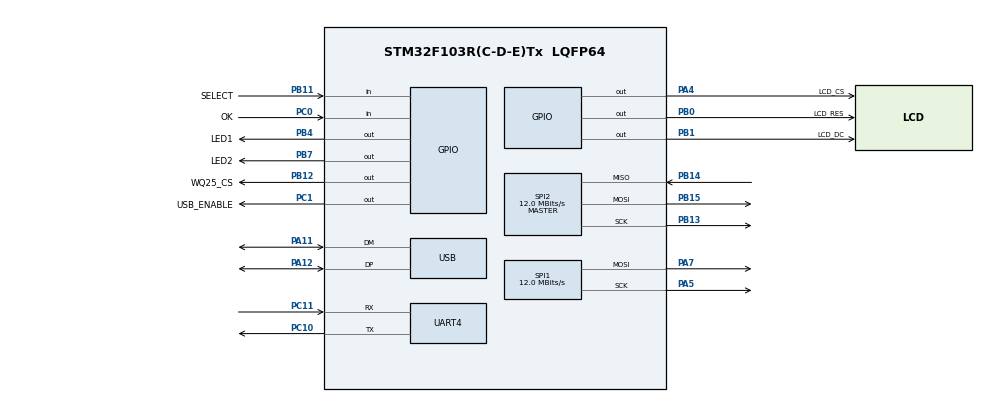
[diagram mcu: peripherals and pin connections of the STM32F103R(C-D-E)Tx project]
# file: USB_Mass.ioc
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Dma.Request0=SPI1_TX
Dma.SPI1_TX.0.Direction=DMA_MEMORY_TO_PERIPH
Dma.SPI1_TX.0.Instance=DMA1_Channel3
Dma.SPI1_TX.0.MemDataAlignment=DMA_MDATAALIGN_BYTE
Dma.SPI1_TX.0.MemInc=DMA_MINC_ENABLE
Dma.SPI1_TX.0.Mode=DMA_NORMAL
Dma.SPI1_TX.0.PeriphDataAlignment=DMA_PDATAALIGN_BYTE
Dma.SPI1_TX.0.PeriphInc=DMA_PINC_DISABLE
Dma.SPI1_TX.0.Priority=DMA_PRIORITY_HIGH
FATFS._MAX_SS=4096
FATFS._MIN_SS=4096
Mcu.Family=STM32F1
Mcu.Name=STM32F103R(C-D-E)Tx
Mcu.Package=LQFP64
NVIC.DMA1_Channel3_IRQn=true\:0\:0\:false\:false\:true\:false\:true\:true
NVIC.PriorityGroup=NVIC_PRIORITYGROUP_4
NVIC.TIM3_IRQn=true\:0\:0\:false\:false\:true\:true\:true\:true
NVIC.USB_LP_CAN1_RX0_IRQn=true\:0\:0\:false\:false\:true\:false\:true\:true
PA11.Mode=Device
PA11.Signal=USB_DM
PA12.Mode=Device
PA12.Signal=USB_DP
PA13.Mode=Serial_Wire
PA13.Signal=SYS_JTMS-SWDIO
PA14.Mode=Serial_Wire
PA14.Signal=SYS_JTCK-SWCLK
PA4.GPIO_Label=LCD_CS
PA4.GPIO_Speed=GPIO_SPEED_FREQ_HIGH
PA4.Signal=GPIO_Output
PA5.Mode=TX_Only_Simplex_Unidirect_Master
PA5.Signal=SPI1_SCK
PA7.Mode=TX_Only_Simplex_Unidirect_Master
PA7.Signal=SPI1_MOSI
PB0.GPIO_Label=LCD_RES
PB0.GPIO_Speed=GPIO_SPEED_FREQ_HIGH
PB0.Signal=GPIO_Output
PB1.GPIO_Label=LCD_DC
PB1.GPIO_Speed=GPIO_SPEED_FREQ_HIGH
PB1.Signal=GPIO_Output
PB11.GPIO_Label=SELECT
PB11.GPIO_PuPd=GPIO_PULLUP
PB11.Signal=GPIO_Input
PB12.GPIO_Label=WQ25_CS
PB12.GPIO_Speed=GPIO_SPEED_FREQ_HIGH
PB12.Signal=GPIO_Output
PB13.Mode=Full_Duplex_Master
PB13.Signal=SPI2_SCK
PB14.Mode=Full_Duplex_Master
PB14.Signal=SPI2_MISO
PB15.Mode=Full_Duplex_Master
PB15.Signal=SPI2_MOSI
PB4.GPIO_Label=LED1
PB4.GPIO_Speed=GPIO_SPEED_FREQ_HIGH
PB4.PinState=GPIO_PIN_SET
PB4.Signal=GPIO_Output
PB7.GPIO_Label=LED2
PB7.GPIO_Speed=GPIO_SPEED_FREQ_HIGH
PB7.PinState=GPIO_PIN_SET
PB7.Signal=GPIO_Output
PC0.GPIO_Label=OK
PC0.GPIO_PuPd=GPIO_PULLUP
PC0.Signal=GPIO_Input
PC1.GPIO_Label=USB_ENABLE
PC1.GPIO_Speed=GPIO_SPEED_FREQ_HIGH
PC1.PinState=GPIO_PIN_RESET
PC1.Signal=GPIO_Output
PC10.Mode=Asynchronous
PC10.Signal=UART4_TX
PC11.Mode=Asynchronous
PC11.Signal=UART4_RX
PD0-OSC_IN.Mode=HSE-External-Oscillator
PD0-OSC_IN.Signal=RCC_OSC_IN
PD1-OSC_OUT.Mode=HSE-External-Oscillator
PD1-OSC_OUT.Signal=RCC_OSC_OUT
ProjectManager.HeapSize=0x200
ProjectManager.StackSize=0x400
ProjectManager.TargetToolchain=MDK-ARM V5.32
RCC.AHBFreq_Value=48000000
RCC.APB1CLKDivider=RCC_HCLK_DIV2
RCC.APB1Freq_Value=24000000
RCC.APB1TimFreq_Value=48000000
RCC.APB2Freq_Value=48000000
RCC.APB2TimFreq_Value=48000000
RCC.HCLKFreq_Value=48000000
RCC.PLLMUL=RCC_PLL_MUL6
RCC.SYSCLKFreq_VALUE=48000000
RCC.SYSCLKSource=RCC_SYSCLKSOURCE_PLLCLK
RCC.USBFreq_Value=48000000
SPI1.BaudRatePrescaler=SPI_BAUDRATEPRESCALER_4
SPI1.CLKPhase=SPI_PHASE_2EDGE
SPI1.CLKPolarity=SPI_POLARITY_HIGH
SPI1.CRCCalculation=SPI_CRCCALCULATION_DISABLE
SPI1.CalculateBaudRate=12.0 MBits/s
SPI1.DataSize=SPI_DATASIZE_8BIT
SPI1.Direction=SPI_DIRECTION_2LINES
SPI1.Mode=SPI_MODE_MASTER
SPI1.VirtualType=VM_MASTER
SPI2.BaudRatePrescaler=SPI_BAUDRATEPRESCALER_2
SPI2.CLKPhase=SPI_PHASE_2EDGE
SPI2.CLKPolarity=SPI_POLARITY_HIGH
SPI2.CalculateBaudRate=12.0 MBits/s
SPI2.Direction=SPI_DIRECTION_2LINES
SPI2.Mode=SPI_MODE_MASTER
SPI2.VirtualType=VM_MASTER
TIM3.Period=1000-1
TIM3.Prescaler=48-1
UART4.VirtualMode=Asynchronous
USB_DEVICE.CLASS_NAME_FS=MSC
USB_DEVICE.MSC_MEDIA_PACKET=4096
USB_DEVICE.VirtualMode=Msc
USB_DEVICE.VirtualModeFS=Msc_FS
VP_FATFS_VS_Generic.Mode=User_defined
VP_TIM3_VS_ClockSourceINT.Mode=Internal
VP_USB_DEVICE_VS_USB_DEVICE_MSC_FS.Mode=MSC_FS
board=custom

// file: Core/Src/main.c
/* USER CODE BEGIN Header */
/**
  ******************************************************************************
  * @file           : main.c
  * @brief          : Main program body
  ******************************************************************************
  * @attention
  *
  * Copyright (c) 2025 STMicroelectronics.
  * All rights reserved.
  *
  * This software is licensed under terms that can be found in the LICENSE file
  * in the root directory of this software component.
  * If no LICENSE file comes with this software, it is provided AS-IS.
  *
  ******************************************************************************
  */
/* USER CODE END Header */
#include "main.h"
#include "dma.h"
#include "fatfs.h"
#include "spi.h"
#include "tim.h"
#include "usart.h"
#include "usb_device.h"
#include "gpio.h"

/* USER CODE BEGIN Includes */
#include "w25qxx.h"
#include "lvgl_ui.h"
#include "json_app.h"
#include "hal/lv_hal_tick.h"
#include "usbd_cdc_if.h"
#include <string.h>
#include <stdio.h>

/* FreeRTOS 头文件 */
#include "FreeRTOS.h"
#include "task.h"
#include "semphr.h"
/* 文件服务 */
#include "app_file_service.h"
/* LVGL 和 LCD 函数声明 */
#include "lvgl.h"
#include "lv_port_disp.h"
#include "lv_port_indev.h"
#include "lcd_init.h"
/* USER CODE END Includes */

/* USER CODE BEGIN PM */
uint8_t file_res;
uint8_t flag = 0;
uint8_t file_res_1;
uint8_t file_res_2;
uint8_t file_res_3;
FILINFO FileInfo = {0};
DIR DirInfo;
DIR User_DirInfo;
FATFS fs; /* Work area (file system object) for logical drives */
FRESULT Res;
UINT br, bw; /* File R/W count */
BYTE work[_MAX_SS];
uint8_t Ctrl_CDC=0;

/* FreeRTOS 任务句柄 */
static TaskHandle_t lvgl_task_handle = NULL;
TaskHandle_t g_cdc_tx_task_handle = NULL;  /* 全局，用于 ISR 通知 */
/* USER CODE END PM */

void SystemClock_Config(void);
/* USER CODE BEGIN PFP */
static void LvglTask(void *argument);
static void CdcTxTask(void *argument);
static void LedTask(void *argument);
/* USER CODE END PFP */

/* USER CODE BEGIN 0 */
#if _USE_LFN
WCHAR ff_convert(WCHAR chr, UINT dir)
{
    if (dir == 0) {
        // 多字节(ASCII) → UTF-16：直接返回（ASCII编码值=UTF-16低字节）
        return (chr <= 0x7F) ? chr : 0;
    } else {
        // UTF-16 → 多字节(ASCII)：仅返回低字节（过滤非ASCII字符）
        return (chr <= 0x7F) ? chr : 0;
    }
}

WCHAR ff_wtoupper (WCHAR chr)
{
    // 判断是否为小写英文字母（UTF-16中a-z的编码为0x0061~0x007A）
    if (chr >= 0x0061 && chr <= 0x007A) {
        return chr - 0x0020;  // 转为大写（A-Z：0x0041~0x005A）
    }
    // 其他字符（数字、符号、中文等）不转换，原样返回
    return chr;
}
#endif
/* USER CODE END 0 */

int main(void)
{

    /* MCU Configuration--------------------------------------------------------*/

    /* Reset of all peripherals, Initializes the Flash interface and the Systick. */
    HAL_Init();

    /* Configure the system clock */
    SystemClock_Config();

    /* Initialize all configured peripherals */
    MX_GPIO_Init();
    MX_DMA_Init();
    MX_SPI2_Init();
    MX_UART4_Init();
    MX_FATFS_Init();
    MX_TIM3_Init();
    HAL_TIM_Base_Start_IT(&htim3);  /* 必须先启动 TIM3，HAL_Delay 依赖它 */
    MX_USB_DEVICE_Init();
    MX_SPI1_Init();
    /* USER CODE BEGIN 2 */

    SPI_FLASH_CS_HIGH();
    W25QXX_TYPE = SPI_FLASH_ReadID();

    file_res = f_mount(&fs, "0:", 1);
    if (FR_NO_FILESYSTEM == file_res)
    {
        flag = 1;
        file_res_1 = f_mkfs("0:", 0, sizeof(work));
        file_res_2 = f_mount(NULL, "0:", 1);
        file_res_3 = f_mount(&fs, "0:", 1);
    }
    HAL_GPIO_WritePin(USB_ENABLE_GPIO_Port, USB_ENABLE_Pin, GPIO_PIN_RESET);
    HAL_Delay(50);  /* 等待主机检测到 USB D+ 上拉 */

    LCD_Init();
    lv_init();            // LVGL 初始化
    lv_port_disp_init();  // 注册LVGL的显示任务
    lv_port_indev_init(); // 按键注册

    create_test_ui();

    if (f_opendir(&DirInfo, (const TCHAR *)"0:") == FR_OK) /* 打开文件夹目录成功，目录信息已经在dir结构体中保存 */
        f_readdir(&DirInfo, &FileInfo); /* 读文件信息到文件状态结构体中 */

//    test_json_parser(); // 测试 json_parser

    /* USER CODE END 2 */

    /* Infinite loop */
    /* USER CODE BEGIN WHILE */
    /* CDC 接收计数信号量（用于 ISR→Task 数据传递）*/
    CDC_Init();

    /* 初始化文件服务任务（优先级 1，用于 FATFS 操作）*/
    FS_Init();

    /* 学习点：FreeRTOS 启动流程
     *
     * 1. xTaskCreate() — 创建任务
     *    参数：任务函数，任务名，栈深度(words)，参数，优先级，任务句柄
     *    LVGL 任务优先级设为 2（空闲任务=0，定时器服务任务=4）
     *
     * 2. vTaskStartScheduler() — 启动 FreeRTOS 调度器
     *    此函数会创建空闲任务和定时器服务任务（如果启用），
     *    然后通过 SVC 异常启动第一个任务。
     *    调用后不会再返回！
     */
    xTaskCreate(
        LvglTask,
        "LVGL",
        440,
        NULL,
        2,
        &lvgl_task_handle
    );

    /* 学习点：CDC TX 任务使用任务通知替代轮询
     * 优先级 3 > LVGL(2)，确保 USB 回传低延迟
     * 当无数据时阻塞在 ulTaskNotifyTake，不消耗 CPU */
    xTaskCreate(
        CdcTxTask,
        "CDC_TX",
        256,
        NULL,
        3,
        &g_cdc_tx_task_handle
    );

    xTaskCreate(
        LedTask,
        "LED",
        80,
        NULL,
        1,
        NULL
    );

    vTaskStartScheduler();  /* 启动调度器，不会返回 */

    /* 如果执行到这里说明 FreeRTOS 堆内存不足 */
    Error_Handler();
    /* USER CODE END WHILE */

}

void SystemClock_Config(void)
{
    RCC_OscInitTypeDef RCC_OscInitStruct = {0};
    RCC_ClkInitTypeDef RCC_ClkInitStruct = {0};
    RCC_PeriphCLKInitTypeDef PeriphClkInit = {0};

    /** Initializes the RCC Oscillators according to the specified parameters
     * in the RCC_OscInitTypeDef structure.
     */
    RCC_OscInitStruct.OscillatorType = RCC_OSCILLATORTYPE_HSE;
    RCC_OscInitStruct.HSEState = RCC_HSE_ON;
    RCC_OscInitStruct.HSEPredivValue = RCC_HSE_PREDIV_DIV1;
    RCC_OscInitStruct.HSIState = RCC_HSI_ON;
    RCC_OscInitStruct.PLL.PLLState = RCC_PLL_ON;
    RCC_OscInitStruct.PLL.PLLSource = RCC_PLLSOURCE_HSE;
    RCC_OscInitStruct.PLL.PLLMUL = RCC_PLL_MUL9;
    if (HAL_RCC_OscConfig(&RCC_OscInitStruct) != HAL_OK)
    {
        Error_Handler();
    }

    /** Initializes the CPU, AHB and APB buses clocks
     */
    RCC_ClkInitStruct.ClockType = RCC_CLOCKTYPE_HCLK | RCC_CLOCKTYPE_SYSCLK | RCC_CLOCKTYPE_PCLK1 | RCC_CLOCKTYPE_PCLK2;
    RCC_ClkInitStruct.SYSCLKSource = RCC_SYSCLKSOURCE_PLLCLK;
    RCC_ClkInitStruct.AHBCLKDivider = RCC_SYSCLK_DIV1;
    RCC_ClkInitStruct.APB1CLKDivider = RCC_HCLK_DIV2;
    RCC_ClkInitStruct.APB2CLKDivider = RCC_HCLK_DIV1;

    if (HAL_RCC_ClockConfig(&RCC_ClkInitStruct, FLASH_LATENCY_2) != HAL_OK)
    {
        Error_Handler();
    }
    PeriphClkInit.PeriphClockSelection = RCC_PERIPHCLK_USB;
    PeriphClkInit.UsbClockSelection = RCC_USBCLKSOURCE_PLL_DIV1_5;  /* 72MHz / 1.5 = 48MHz */
    if (HAL_RCCEx_PeriphCLKConfig(&PeriphClkInit) != HAL_OK)
    {
        Error_Handler();
    }
}

/* USER CODE BEGIN 4 */

/**
  * @brief LVGL 任务函数
  *
  * 学习点：这是一个 FreeRTOS 任务函数，具有以下特征：
  * - 无限循环，永不返回
  * - vTaskDelay() 让任务进入阻塞态，释放 CPU 给其他任务或空闲任务
  * - 对比原来 main loop 的 systemTick 轮询方式，vTaskDelay 更高效
  *   （阻塞期间 CPU 可以执行其他任务或进入低功耗）
  */
static void LvglTask(void *argument)
{
    (void)argument;

    while (1)
    {
        lv_timer_handler();   /* 处理 LVGL 内部定时任务（渲染、动画等）*/
        vTaskDelay(pdMS_TO_TICKS(5));  /* 阻塞 5ms，让出 CPU */
    }
}

/**
  * @brief LED 闪烁任务
  *        优先级 1，每 500ms 翻转一次 LED1(PB4)
  */
static void LedTask(void *argument)
{
    (void)argument;

    while (1)
    {
        // TODO: 在这里翻转 LED1（PB4）
        // 提示：HAL_GPIO_TogglePin(LED1_GPIO_Port, LED1_Pin);
        HAL_GPIO_TogglePin(LED1_GPIO_Port, LED1_Pin);
        vTaskDelay(pdMS_TO_TICKS(500));
    }
}

/**
  * @brief CDC TX 任务函数
  *
  * 学习点：使用 FreeRTOS 任务通知替代固定间隔轮询。
  * ulTaskNotifyTake() 使任务阻塞，零 CPU 消耗；
  * USB ISR 通过 vTaskNotifyGiveFromISR() 唤醒任务，
  * 实现数据到达 → 立即发送，无需等待下一个轮询周期。
  *
  * 优先级 3（高于 LVGL 的 2），确保 USB 回传低延迟。
  */
static void CdcTxTask(void *argument)
{
    (void)argument;

    while (1)
    {
        /* 阻塞等待计数信号量 — 有新数据到达时 ISR 会递增计数值 */
        xSemaphoreTake(g_rx_sem, portMAX_DELAY);

        CDC_ProcessTx();
    }
}

/**
  * @brief TIM3 周期中断回调 — 为 LVGL 提供 1ms tick
  * HAL 时间基准由 SysTick 提供
  */
void HAL_TIM_PeriodElapsedCallback(TIM_HandleTypeDef *htim)
{
    if (htim->Instance == htim3.Instance)
    {
        lv_tick_inc(1);
    }
}

/* SPI 传输完成回调函数 */
void HAL_SPI_TxRxCpltCallback(SPI_HandleTypeDef *hspi)
{
    if (hspi->Instance == SPI1)
    {
        /* 传输完成，可以在这里处理接收到的数据 */
    }
}
/* USER CODE END 4 */

void Error_Handler(void)
{
    __disable_irq();
    while (1)
    {
    }
}
